VERSION 5.7 ;
  NOWIREEXTENSIONATPIN ON ;
  DIVIDERCHAR "/" ;
  BUSBITCHARS "[]" ;
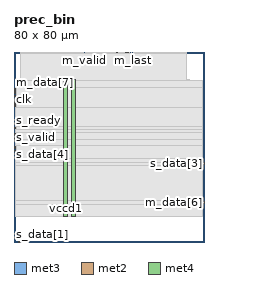
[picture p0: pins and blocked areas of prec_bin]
MACRO prec_bin
  CLASS BLOCK ;
  FOREIGN prec_bin ;
  ORIGIN 0.000 0.000 ;
  SIZE 80.000 BY 80.000 ;
  PIN clk
    DIRECTION INPUT ;
    USE SIGNAL ;
    ANTENNAGATEAREA 1.286700 ;
    ANTENNADIFFAREA 0.434700 ;
    PORT
      LAYER met3 ;
        RECT 0.000 59.880 0.600 60.480 ;
    END
  END clk
  PIN m_data[0]
    DIRECTION OUTPUT ;
    USE SIGNAL ;
    ANTENNADIFFAREA 0.795200 ;
    PORT
      LAYER met2 ;
        RECT 48.850 79.720 49.130 80.000 ;
    END
  END m_data[0]
  PIN m_data[1]
    DIRECTION OUTPUT ;
    USE SIGNAL ;
    ANTENNADIFFAREA 0.795200 ;
    PORT
      LAYER met2 ;
        RECT 43.330 79.720 43.610 80.000 ;
    END
  END m_data[1]
  PIN m_data[2]
    DIRECTION OUTPUT ;
    USE SIGNAL ;
    ANTENNADIFFAREA 0.795200 ;
    PORT
      LAYER met2 ;
        RECT 47.930 79.720 48.210 80.000 ;
    END
  END m_data[2]
  PIN m_data[3]
    DIRECTION OUTPUT ;
    USE SIGNAL ;
    ANTENNADIFFAREA 0.795200 ;
    PORT
      LAYER met2 ;
        RECT 47.010 79.720 47.290 80.000 ;
    END
  END m_data[3]
  PIN m_data[4]
    DIRECTION OUTPUT ;
    USE SIGNAL ;
    PORT
      LAYER met3 ;
        RECT 0.000 61.240 0.600 61.840 ;
    END
  END m_data[4]
  PIN m_data[5]
    DIRECTION OUTPUT ;
    USE SIGNAL ;
    PORT
      LAYER met3 ;
        RECT 0.000 62.600 0.600 63.200 ;
    END
  END m_data[5]
  PIN m_data[6]
    DIRECTION OUTPUT ;
    USE SIGNAL ;
    PORT
      LAYER met3 ;
        RECT 79.400 16.360 80.000 16.960 ;
    END
  END m_data[6]
  PIN m_data[7]
    DIRECTION OUTPUT ;
    USE SIGNAL ;
    PORT
      LAYER met3 ;
        RECT 0.000 63.960 0.600 64.560 ;
    END
  END m_data[7]
  PIN m_last
    DIRECTION OUTPUT ;
    USE SIGNAL ;
    ANTENNADIFFAREA 0.795200 ;
    PORT
      LAYER met2 ;
        RECT 49.770 79.720 50.050 80.000 ;
    END
  END m_last
  PIN m_ready
    DIRECTION INPUT ;
    USE SIGNAL ;
    ANTENNAGATEAREA 0.647700 ;
    ANTENNADIFFAREA 0.434700 ;
    PORT
      LAYER met3 ;
        RECT 0.000 58.520 0.600 59.120 ;
    END
  END m_ready
  PIN m_valid
    DIRECTION OUTPUT ;
    USE SIGNAL ;
    ANTENNADIFFAREA 0.795200 ;
    PORT
      LAYER met2 ;
        RECT 29.530 79.720 29.810 80.000 ;
    END
  END m_valid
  PIN rst
    DIRECTION INPUT ;
    USE SIGNAL ;
    ANTENNAGATEAREA 0.647700 ;
    ANTENNADIFFAREA 0.434700 ;
    PORT
      LAYER met3 ;
        RECT 0.000 57.160 0.600 57.760 ;
    END
  END rst
  PIN s_data[0]
    DIRECTION INPUT ;
    USE SIGNAL ;
    PORT
      LAYER met2 ;
        RECT 1.930 0.000 2.210 0.280 ;
    END
  END s_data[0]
  PIN s_data[1]
    DIRECTION INPUT ;
    USE SIGNAL ;
    PORT
      LAYER met2 ;
        RECT 2.850 0.000 3.130 0.280 ;
    END
  END s_data[1]
  PIN s_data[2]
    DIRECTION INPUT ;
    USE SIGNAL ;
    PORT
      LAYER met2 ;
        RECT 3.770 0.000 4.050 0.280 ;
    END
  END s_data[2]
  PIN s_data[3]
    DIRECTION INPUT ;
    USE SIGNAL ;
    ANTENNAGATEAREA 0.647700 ;
    ANTENNADIFFAREA 0.434700 ;
    PORT
      LAYER met3 ;
        RECT 79.400 32.680 80.000 33.280 ;
    END
  END s_data[3]
  PIN s_data[4]
    DIRECTION INPUT ;
    USE SIGNAL ;
    ANTENNAGATEAREA 0.647700 ;
    ANTENNADIFFAREA 0.434700 ;
    PORT
      LAYER met3 ;
        RECT 0.000 39.480 0.600 40.080 ;
    END
  END s_data[4]
  PIN s_data[5]
    DIRECTION INPUT ;
    USE SIGNAL ;
    ANTENNAGATEAREA 0.647700 ;
    ANTENNADIFFAREA 0.434700 ;
    PORT
      LAYER met3 ;
        RECT 0.000 36.760 0.600 37.360 ;
    END
  END s_data[5]
  PIN s_data[6]
    DIRECTION INPUT ;
    USE SIGNAL ;
    ANTENNAGATEAREA 0.647700 ;
    ANTENNADIFFAREA 0.434700 ;
    PORT
      LAYER met3 ;
        RECT 0.000 35.400 0.600 36.000 ;
    END
  END s_data[6]
  PIN s_data[7]
    DIRECTION INPUT ;
    USE SIGNAL ;
    ANTENNAGATEAREA 0.647700 ;
    ANTENNADIFFAREA 0.434700 ;
    PORT
      LAYER met3 ;
        RECT 0.000 38.120 0.600 38.720 ;
    END
  END s_data[7]
  PIN s_last
    DIRECTION INPUT ;
    USE SIGNAL ;
    ANTENNAGATEAREA 0.647700 ;
    ANTENNADIFFAREA 0.434700 ;
    PORT
      LAYER met3 ;
        RECT 0.000 44.920 0.600 45.520 ;
    END
  END s_last
  PIN s_ready
    DIRECTION OUTPUT ;
    USE SIGNAL ;
    ANTENNADIFFAREA 0.795200 ;
    PORT
      LAYER met3 ;
        RECT 0.000 47.640 0.600 48.240 ;
    END
  END s_ready
  PIN s_valid
    DIRECTION INPUT ;
    USE SIGNAL ;
    ANTENNAGATEAREA 0.647700 ;
    ANTENNADIFFAREA 0.434700 ;
    PORT
      LAYER met3 ;
        RECT 0.000 43.560 0.600 44.160 ;
    END
  END s_valid
  PIN vccd1
    DIRECTION INOUT ;
    USE POWER ;
    PORT
      LAYER met4 ;
        RECT 21.040 10.640 22.640 68.240 ;
    END
  END vccd1
  PIN vssd1
    DIRECTION INOUT ;
    USE GROUND ;
    PORT
      LAYER met4 ;
        RECT 24.340 10.640 25.940 68.240 ;
    END
  END vssd1
  OBS
      LAYER nwell ;
        RECT 5.330 10.795 74.250 68.190 ;
      LAYER li1 ;
        RECT 5.520 10.795 74.060 68.085 ;
      LAYER met1 ;
        RECT 2.830 10.640 74.060 68.240 ;
      LAYER met2 ;
        RECT 2.850 79.440 29.250 79.720 ;
        RECT 30.090 79.440 43.050 79.720 ;
        RECT 43.890 79.440 46.730 79.720 ;
        RECT 47.570 79.440 47.650 79.720 ;
        RECT 48.490 79.440 48.570 79.720 ;
        RECT 49.410 79.440 49.490 79.720 ;
        RECT 50.330 79.440 72.590 79.720 ;
        RECT 2.850 10.695 72.590 79.440 ;
      LAYER met3 ;
        RECT 0.600 64.960 79.400 68.165 ;
        RECT 1.000 56.760 79.400 64.960 ;
        RECT 0.600 48.640 79.400 56.760 ;
        RECT 1.000 47.240 79.400 48.640 ;
        RECT 0.600 45.920 79.400 47.240 ;
        RECT 1.000 43.160 79.400 45.920 ;
        RECT 0.600 40.480 79.400 43.160 ;
        RECT 1.000 35.000 79.400 40.480 ;
        RECT 0.600 33.680 79.400 35.000 ;
        RECT 0.600 32.280 79.000 33.680 ;
        RECT 0.600 17.360 79.400 32.280 ;
        RECT 0.600 15.960 79.000 17.360 ;
        RECT 0.600 10.715 79.400 15.960 ;
  END
END prec_bin
END LIBRARY

